! (c) 2009  Infineon Technologies AG, Munich
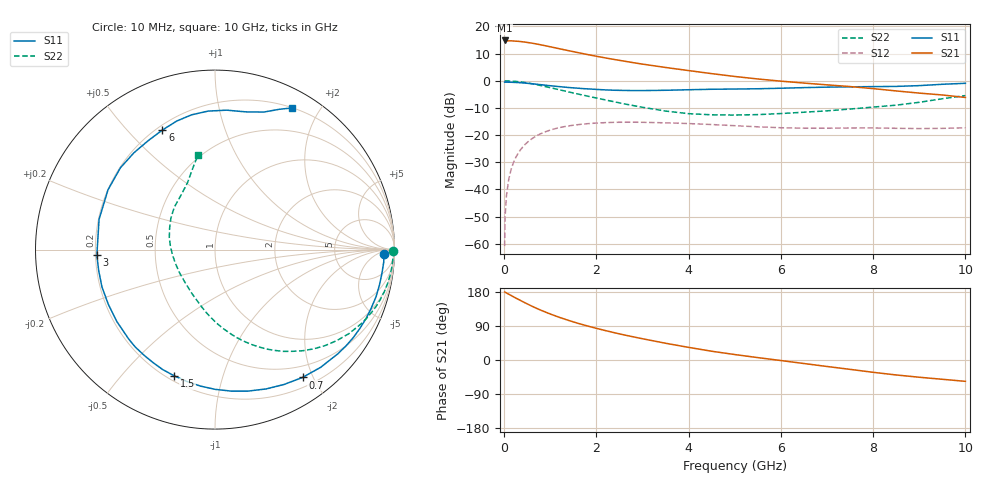
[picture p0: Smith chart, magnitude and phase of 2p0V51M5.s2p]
! Infineon Technologies  Discrete & RF Semiconductors
! BFP420
! VCE =  0.5 V,  IC =  1.5 mA
! Common Emitter S-Parameters:  Nov 2009
# GHz  S  MA  R  50
!  f  S11  S21  S12  S22
! GHz  MAG  ANG  MAG  ANG  MAG  ANG  MAG  ANG
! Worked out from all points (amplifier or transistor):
!   46 points, 10 MHz to 10 GHz, reference 50 ohm
!   highest |S21| = 14.8 dB at 10 MHz (marker M1)
!   |S21| within 3 dB of that: start of sweep to 1.184 GHz
!   unconditionally stable (mu >= 1): 4.162 GHz to end of sweep
!   at 300 MHz: K = 0.04, MSG = 20.7 dB, |S12| = -26.8 dB
!   at 1.7 GHz: K = 0.36, MSG = 13.0 dB, |S12| = -16.0 dB
!   at 10 GHz: K = 1.22, MAG = 2.8 dB, |S12| = -17.3 dB
!   lowest NFmin = 0.52 dB at 900 MHz
!   S11 on the Smith chart (normalised r, x): 10 MHz: 28, -13; 700 MHz: 0.33, -1.85; 1.5 GHz: 0.23, -0.70; 3 GHz: 0.21, -0.02; 6 GHz: 0.22, +0.63; 10 GHz: 0.21, +1.66
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0.01  0.9428 -1.5  5.517 179.4  0.0009 86.4  0.9925 -0.3
0.02  0.941 -1.6  5.365 179.1  0.003 86.5  0.993 -1.1
0.05  0.9428 -4.1  5.399 176.8  0.0077 88.8  0.9928 -2.8
0.15  0.9372 -12.2  5.424 170.3  0.0232 82.4  0.9858 -8.5
0.3  0.9251 -24.4  5.323 160.5  0.0457 74.8  0.9622 -16.8
0.45  0.9057 -36.4  5.151 151.1  0.0667 67.3  0.9261 -24.7
0.6  0.8813 -48.1  4.926 142.1  0.0854 60.2  0.881 -32.1
0.7  0.8631 -55.6  4.758 136.5  0.0965 55.7  0.8476 -36.7
1  0.8095 -76.9  4.221 121.4  0.1236 43.8  0.7455 -49.1
1.2  0.7787 -89.9  3.879 112.4  0.1372 36.9  0.6814 -56.3
1.5  0.7391 -107.9  3.432 100.6  0.1519 27.9  0.5952 -65.7
1.7  0.7174 -119.0  3.172 93.4  0.159 22.6  0.5456 -71.3
2.2  0.6781 -143.7  2.629 77.5  0.1695 11.3  0.4425 -84.0
2.6  0.6634 -161.7  2.297 66.2  0.1723 3.5  0.376 -94.0
3  0.659 -177.3  2.024 56.1  0.1717 -3.1  0.3245 -103.8
3.5  0.6675 165.4  1.755 44.2  0.1679 -10.1  0.2766 -117.6
4.5  0.6968 139.1  1.352 23.1  0.1562 -20.4  0.2359 -147.1
5.5  0.7119 121.6  1.078 6.3  0.1418 -25.9  0.238 -172.2
6  0.7278 113.7  0.983 -1.4  0.1364 -27.1  0.2489 175.9
7  0.7621 99.9  0.84 -17.1  0.1336 -28.4  0.2791 155.0
8.5  0.7865 77.3  0.649 -39.5  0.1331 -33.6  0.3551 122.7
10  0.8971 61.6  0.492 -56.3  0.1359 -34.9  0.5332 100.4
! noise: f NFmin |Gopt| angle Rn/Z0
0.9  0.52  0.55  33  0.27
1.8  1.07  0.35  77  0.21
2.4  1.18  0.36  101  0.18
3  1.41  0.36  134  0.13
4  1.68  0.4  -172  0.1
5  2.08  0.44  -130  0.32
6  2.89  0.57  -114  0.39
